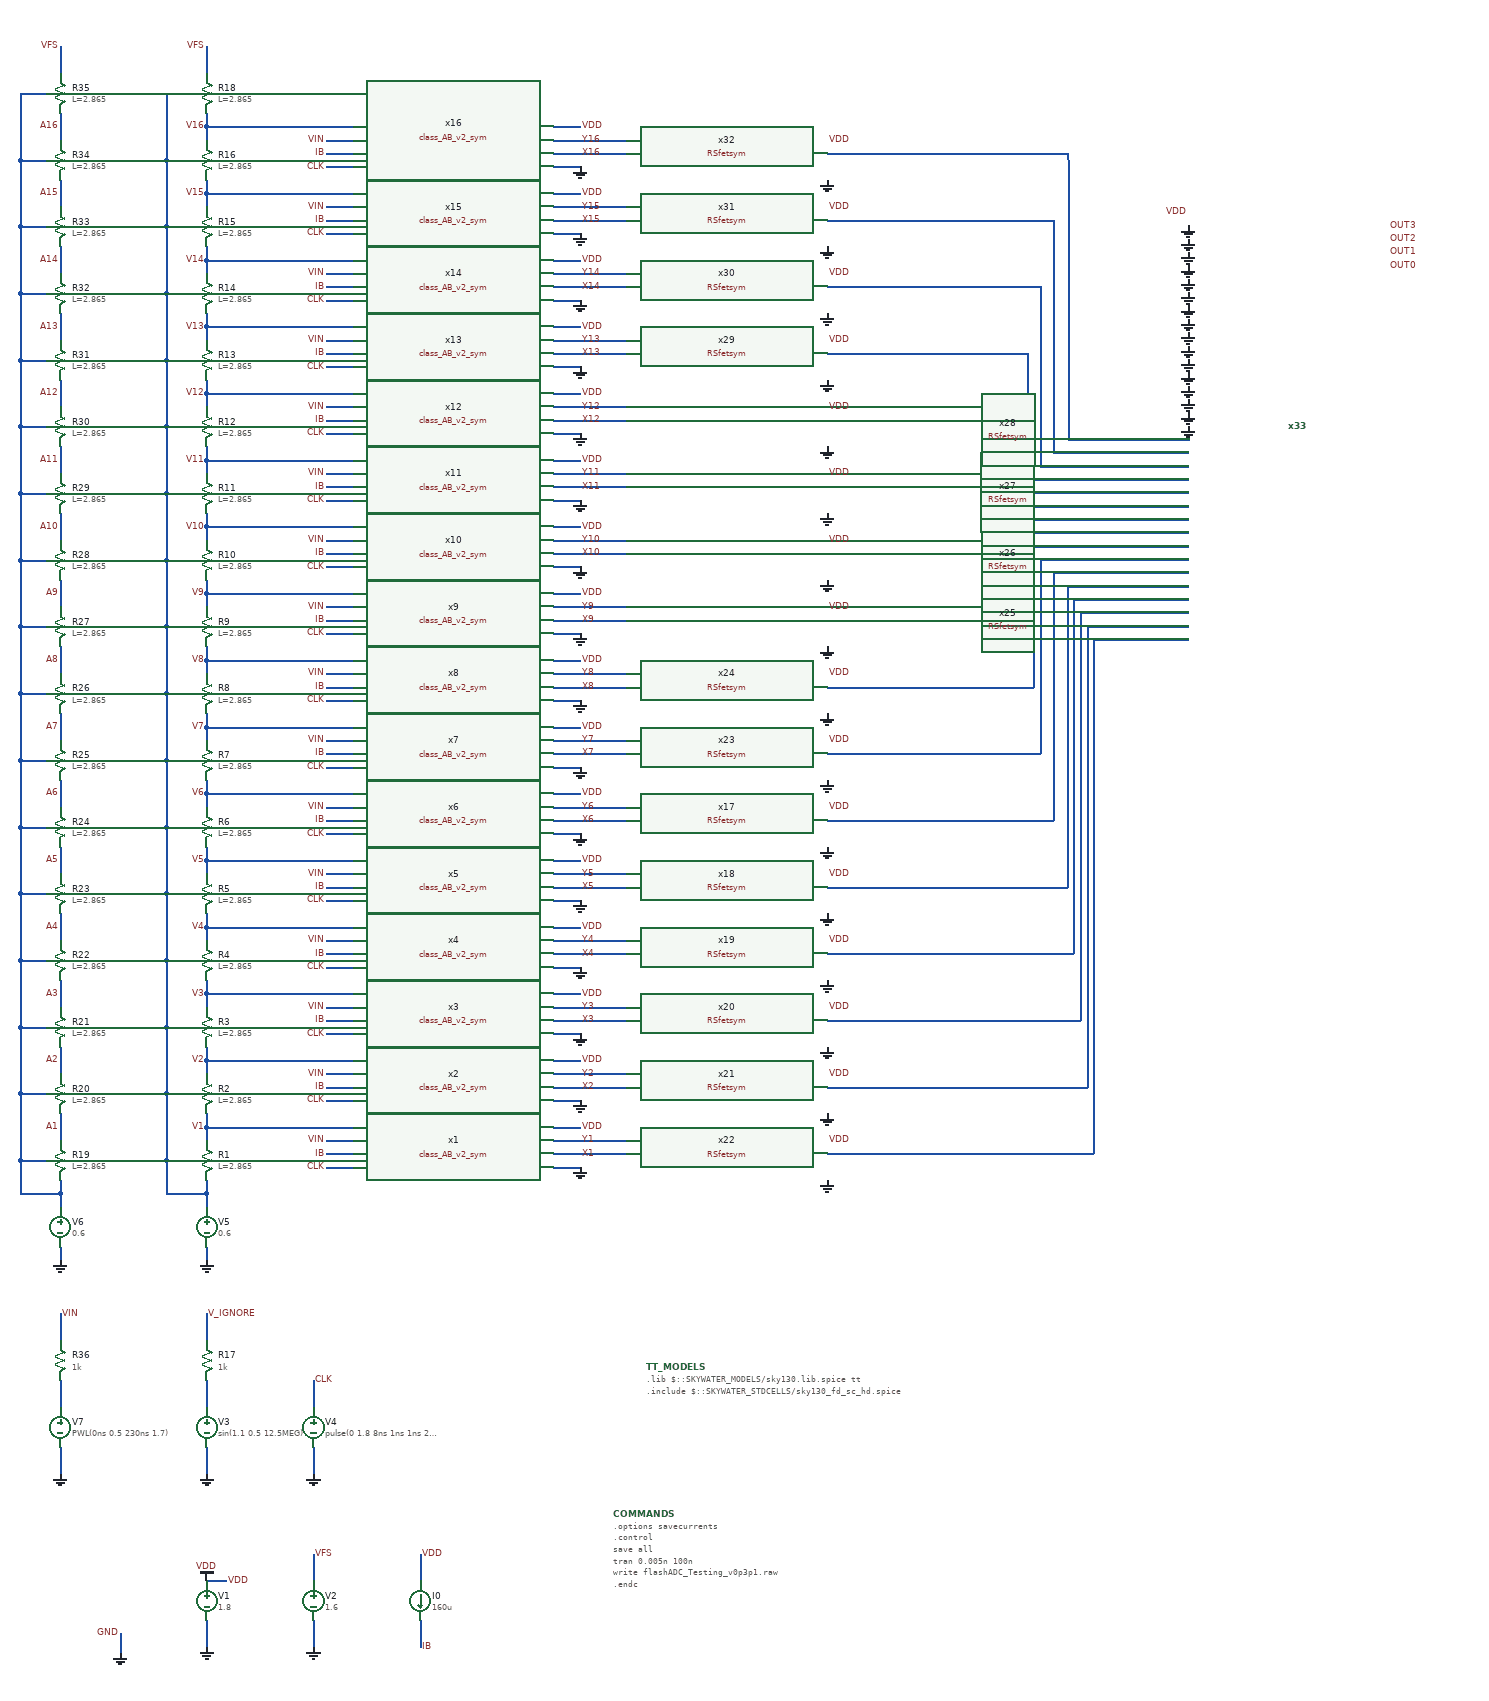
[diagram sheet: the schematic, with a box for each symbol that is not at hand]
v {xschem version=3.4.5 file_version=1.2
}
G {}
K {}
V {}
S {}
E {}
B 2 3025 -2178.75 3825 -1778.75 {flags=graph
y1=-0.36
y2=1.44
ypos1=0
ypos2=2
divy=5
subdivy=1
unity=1
x1=0
x2=1e-07
divx=5
subdivx=1
xlabmag=1.0
ylabmag=1.0


dataset=-1
unitx=1
logx=0
logy=0
color=4
node=clk}
B 2 3025 -2578.75 3825 -2178.75 {flags=graph
y1=-0.0013
y2=1.7
ypos1=0
ypos2=2
divy=5
subdivy=1
unity=1
x1=0
x2=1e-07
divx=5
subdivx=1
xlabmag=1.0
ylabmag=1.0


dataset=-1
unitx=1
logx=0
logy=0
color="4 5 6 8"
node="y1
v1
vin
a1"}
B 2 3025 -2978.75 3825 -2578.75 {flags=graph
y1=-0.0013
y2=1.7
ypos1=0
ypos2=2
divy=5
subdivy=1
unity=1
x1=0
x2=1e-07
divx=5
subdivx=1
xlabmag=1.0
ylabmag=1.0


dataset=-1
unitx=1
logx=0
logy=0




color="4 5 6 8"
node="y2
v2
vin
a2"}
B 2 3025 -3378.75 3825 -2978.75 {flags=graph
y1=-0.0013
y2=1.7
ypos1=0
ypos2=2
divy=5
subdivy=1
unity=1
x1=0
x2=1e-07
divx=5
subdivx=1
xlabmag=1.0
ylabmag=1.0


dataset=-1
unitx=1
logx=0
logy=0
color="4 5 6 8"
node="y3
v3
vin
a3"}
B 2 3025 -3778.75 3825 -3378.75 {flags=graph
y1=-0.0013
y2=1.9
ypos1=0
ypos2=2
divy=5
subdivy=1
unity=1
x1=0
x2=1e-07
divx=5
subdivx=1
xlabmag=1.0
ylabmag=1.0
node="y4
v4
vin
a4"
color="4 5 6 8"
dataset=-1
unitx=1
logx=0
logy=0
}
B 2 3825 -2578.75 4625 -2178.75 {flags=graph
y1=-0.0013
y2=1.9
ypos1=0
ypos2=2
divy=5
subdivy=1
unity=1
x1=0
x2=1e-07
divx=5
subdivx=1
xlabmag=1.0
ylabmag=1.0


dataset=-1
unitx=1
logx=0
logy=0

color="4 5 6 8"
node="y5
v5
vin
a5"}
B 2 3825 -2978.75 4625 -2578.75 {flags=graph
y1=-0.0013
y2=1.9
ypos1=0
ypos2=2
divy=5
subdivy=1
unity=1
x1=0
x2=1e-07
divx=5
subdivx=1
xlabmag=1.0
ylabmag=1.0
node="y6
v6
vin
a6"
color="4 5 6 8"
dataset=-1
unitx=1
logx=0
logy=0
}
B 2 3825 -3378.75 4625 -2978.75 {flags=graph
y1=-0.0013
y2=1.9
ypos1=0
ypos2=2
divy=5
subdivy=1
unity=1
x1=0
x2=1e-07
divx=5
subdivx=1
xlabmag=1.0
ylabmag=1.0


dataset=-1
unitx=1
logx=0
logy=0
color="4 5 6 8"
node="y7
v7
vin
a7"}
B 2 3825 -3778.75 4625 -3378.75 {flags=graph
y1=-0.0013
y2=1.9
ypos1=0
ypos2=2
divy=5
subdivy=1
unity=1
x1=0
x2=1e-07
divx=5
subdivx=1
xlabmag=1.0
ylabmag=1.0


dataset=-1
unitx=1
logx=0
logy=0
color="4 5 6 8"
node="y8
v8
vin
a8"}
B 2 4625 -2578.75 5425 -2178.75 {flags=graph
y1=-0.0013
y2=1.9
ypos1=0
ypos2=2
divy=5
subdivy=1
unity=1
x1=0
x2=1e-07
divx=5
subdivx=1
xlabmag=1.0
ylabmag=1.0


dataset=-1
unitx=1
logx=0
logy=0
color="4 5 6 8"
node="y9
v9
vin
a9"}
B 2 4625 -2978.75 5425 -2578.75 {flags=graph
y1=-0.12
y2=1.9
ypos1=0
ypos2=2
divy=5
subdivy=1
unity=1
x1=0
x2=1e-07
divx=5
subdivx=1
xlabmag=1.0
ylabmag=1.0


dataset=-1
unitx=1
logx=0
logy=0




color="4 5 6 8"
node="y10
v10
vin
a10"}
B 2 4625 -3378.75 5425 -2978.75 {flags=graph
y1=-0.0013
y2=1.9
ypos1=0
ypos2=2
divy=5
subdivy=1
unity=1
x1=0
x2=1e-07
divx=5
subdivx=1
xlabmag=1.0
ylabmag=1.0


dataset=-1
unitx=1
logx=0
logy=0
color="4 5 6 8"
node="y11
v11
vin
a11"}
B 2 4625 -3778.75 5425 -3378.75 {flags=graph
y1=-0.0013
y2=1.9
ypos1=0
ypos2=2
divy=5
subdivy=1
unity=1
x1=0
x2=1e-07
divx=5
subdivx=1
xlabmag=1.0
ylabmag=1.0
node="y12
v12
vin
a12"
color="4 5 6 8"
dataset=-1
unitx=1
logx=0
logy=0
}
B 2 5425 -2578.75 6225 -2178.75 {flags=graph
y1=-0.0011
y2=1.9
ypos1=0
ypos2=2
divy=5
subdivy=1
unity=1
x1=0
x2=1e-07
divx=5
subdivx=1
xlabmag=1.0
ylabmag=1.0


dataset=-1
unitx=1
logx=0
logy=0

color="4 5 6 8"
node="y13
v13
vin
a13"}
B 2 5425 -2978.75 6225 -2578.75 {flags=graph
y1=0.61
y2=1.9
ypos1=0
ypos2=2
divy=5
subdivy=1
unity=1
x1=0
x2=1e-07
divx=5
subdivx=1
xlabmag=1.0
ylabmag=1.0
node="y14
v14
vin
a14"
color="4 5 6 8"
dataset=-1
unitx=1
logx=0
logy=0
}
B 2 5425 -3378.75 6225 -2978.75 {flags=graph
y1=0.6
y2=1.9
ypos1=0
ypos2=2
divy=5
subdivy=1
unity=1
x1=0
x2=1e-07
divx=5
subdivx=1
xlabmag=1.0
ylabmag=1.0


dataset=-1
unitx=1
logx=0
logy=0
color="4 5 6 8"
node="y15
v15
vin
a15"}
B 2 5425 -3778.75 6225 -3378.75 {flags=graph
y1=0.6
y2=1.9
ypos1=0
ypos2=2
divy=5
subdivy=1
unity=1
x1=0
x2=1e-07
divx=5
subdivx=1
xlabmag=1.0
ylabmag=1.0


dataset=-1
unitx=1
logx=0
logy=0
color="4 5 6 8"
node="y16
v16
vin
a16"}
B 2 3825 -2178.75 4625 -1778.75 {flags=graph
y1=0
y2=1.8
ypos1=0
ypos2=2
divy=5
subdivy=1
unity=1
x1=0
x2=1e-07
divx=5
subdivx=1
xlabmag=1.0
ylabmag=1.0


dataset=-1
unitx=1
logx=0
logy=0
color=4
node=clk}
B 2 4625 -2178.75 5425 -1778.75 {flags=graph
y1=0
y2=1.8
ypos1=0
ypos2=2
divy=5
subdivy=1
unity=1
x1=0
x2=1e-07
divx=5
subdivx=1
xlabmag=1.0
ylabmag=1.0


dataset=-1
unitx=1
logx=0
logy=0
color=4
node=clk}
B 2 5425 -2178.75 6225 -1778.75 {flags=graph
y1=0
y2=1.8
ypos1=0
ypos2=2
divy=5
subdivy=1
unity=1
x1=0
x2=1e-07
divx=5
subdivx=1
xlabmag=1.0
ylabmag=1.0


dataset=-1
unitx=1
logx=0
logy=0
color=4
node=clk}
B 2 6225 -2578.75 7025 -2178.75 {flags=graph
y1=1.3
y2=1.4
ypos1=0
ypos2=2
divy=5
subdivy=1
unity=1
x1=0
x2=1e-07
divx=5
subdivx=1
xlabmag=1.0
ylabmag=1.0


dataset=-1
unitx=1
logx=0
logy=0

color="4 8"
node="v13
a13"}
B 2 1985 -4078.75 2785 -3678.75 {flags=graph
y1=-0.0013
y2=1.9
ypos1=0
ypos2=2
divy=5
subdivy=1
unity=1
x1=0
x2=1e-07
divx=5
subdivx=1
xlabmag=1.0
ylabmag=1.0
node="y6
x6
y6q
x6!q
Vin"
color="4 5 10 8 6"
dataset=-1
unitx=1
logx=0
logy=0
hilight_wave=3}
B 2 3025 -1208.75 3825 -808.75 {flags=graph
y1=-0.15
y2=2.1
ypos1=0
ypos2=2
divy=5
subdivy=1
unity=1
x1=0
x2=1e-07
divx=5
subdivx=1
xlabmag=1.0
ylabmag=1.0


dataset=-1
unitx=1
logx=0
logy=0

color="7 21 8 4"
node="out3
out2
out1
out0"}
B 2 3026.25 -1761.25 3825 -1318.75 {flags=graph
y1=0
y2=1.8
ypos1=0
ypos2=2
divy=5
subdivy=1
unity=1
x1=0
x2=1e-07
divx=5
subdivx=1
xlabmag=1.0
ylabmag=1.0


dataset=-1
unitx=1
logx=0
logy=0
color=4
node=clk
hilight_wave=0}
N 235 -428.75 235 -408.75 {
lab=V2}
N 235 -328.75 235 -308.75 {
lab=V1}
N 235 -228.75 235 -208.75 {
lab=#net1}
N 235 -528.75 235 -508.75 {
lab=V3}
N 235 -628.75 235 -608.75 {
lab=V4}
N 235 -728.75 235 -708.75 {
lab=V5}
N 235 -828.75 235 -808.75 {
lab=V6}
N 235 -928.75 235 -908.75 {
lab=V7}
N 235 -1028.75 235 -1008.75 {
lab=V8}
N 235 -1128.75 235 -1108.75 {
lab=V9}
N 235 -1228.75 235 -1208.75 {
lab=V10}
N 235 -1328.75 235 -1308.75 {
lab=V11}
N 235 -1428.75 235 -1408.75 {
lab=V12}
N 235 -1528.75 235 -1508.75 {
lab=V13}
N 235 -1628.75 235 -1608.75 {
lab=V14}
N 235 -1728.75 235 -1708.75 {
lab=V15}
N 235 -1828.75 235 -1808.75 {
lab=V16}
N 175 -1778.75 215 -1778.75 {
lab=#net1}
N 175 -1778.75 175 -1678.75 {
lab=#net1}
N 175 -1678.75 215 -1678.75 {
lab=#net1}
N 175 -1578.75 215 -1578.75 {
lab=#net1}
N 175 -1478.75 215 -1478.75 {
lab=#net1}
N 175 -1378.75 215 -1378.75 {
lab=#net1}
N 175 -1278.75 215 -1278.75 {
lab=#net1}
N 175 -1178.75 215 -1178.75 {
lab=#net1}
N 175 -1078.75 215 -1078.75 {
lab=#net1}
N 175 -978.75 215 -978.75 {
lab=#net1}
N 175 -878.75 215 -878.75 {
lab=#net1}
N 175 -778.75 215 -778.75 {
lab=#net1}
N 175 -678.75 215 -678.75 {
lab=#net1}
N 175 -578.75 215 -578.75 {
lab=#net1}
N 175 -478.75 215 -478.75 {
lab=#net1}
N 175 -378.75 215 -378.75 {
lab=#net1}
N 175 -278.75 215 -278.75 {
lab=#net1}
N 175 -228.75 235 -228.75 {
lab=#net1}
N 175 -278.75 175 -228.75 {
lab=#net1}
N 175 -478.75 175 -378.75 {
lab=#net1}
N 175 -578.75 175 -478.75 {
lab=#net1}
N 235 51.25 235 91.25 {
lab=#net2}
N 235 151.25 235 191.25 {
lab=GND}
N 395 51.25 395 91.25 {
lab=CLK}
N 395 151.25 395 191.25 {
lab=GND}
N 235 351.25 265 351.25 {
lab=VDD}
N 235 411.25 235 451.25 {
lab=GND}
N 395 311.25 395 351.25 {
lab=VFS}
N 395 411.25 395 451.25 {
lab=GND}
N 235 -48.75 235 -8.75 {
lab=V_IGNORE}
N 235 -328.75 455 -328.75 {
lab=V1}
N 235 -1948.75 235 -1908.75 {
lab=VFS}
N 175 -1878.75 215 -1878.75 {
lab=#net1}
N 175 -1878.75 175 -1778.75 {
lab=#net1}
N 415 -288.75 455 -288.75 {
lab=IB}
N 415 -308.75 455 -308.75 {
lab=VIN}
N 755 -328.75 795 -328.75 {
lab=VDD}
N 755 -308.75 865 -308.75 {
lab=Y1}
N 755 -288.75 865 -288.75 {
lab=X1}
N 755 -268.75 795 -268.75 {
lab=GND}
N 755 -428.75 795 -428.75 {
lab=VDD}
N 755 -408.75 865 -408.75 {
lab=Y2}
N 755 -388.75 865 -388.75 {
lab=X2}
N 755 -368.75 795 -368.75 {
lab=GND}
N 755 -528.75 795 -528.75 {
lab=VDD}
N 755 -508.75 865 -508.75 {
lab=Y3}
N 755 -488.75 865 -488.75 {
lab=X3}
N 755 -468.75 795 -468.75 {
lab=GND}
N 755 -628.75 795 -628.75 {
lab=VDD}
N 755 -608.75 865 -608.75 {
lab=Y4}
N 755 -588.75 865 -588.75 {
lab=X4}
N 755 -568.75 795 -568.75 {
lab=GND}
N 755 -728.75 795 -728.75 {
lab=VDD}
N 755 -708.75 865 -708.75 {
lab=Y5}
N 755 -688.75 865 -688.75 {
lab=X5}
N 755 -668.75 795 -668.75 {
lab=GND}
N 755 -828.75 795 -828.75 {
lab=VDD}
N 755 -808.75 865 -808.75 {
lab=Y6}
N 755 -788.75 865 -788.75 {
lab=X6}
N 755 -768.75 795 -768.75 {
lab=GND}
N 755 -928.75 795 -928.75 {
lab=VDD}
N 755 -908.75 865 -908.75 {
lab=Y7}
N 755 -888.75 865 -888.75 {
lab=X7}
N 755 -868.75 795 -868.75 {
lab=GND}
N 755 -1028.75 795 -1028.75 {
lab=VDD}
N 755 -1008.75 865 -1008.75 {
lab=Y8}
N 755 -988.75 865 -988.75 {
lab=X8}
N 755 -968.75 795 -968.75 {
lab=GND}
N 755 -1128.75 795 -1128.75 {
lab=VDD}
N 755 -1108.75 865 -1108.75 {
lab=Y9}
N 755 -1088.75 865 -1088.75 {
lab=X9}
N 755 -1068.75 795 -1068.75 {
lab=GND}
N 755 -1228.75 795 -1228.75 {
lab=VDD}
N 755 -1208.75 865 -1208.75 {
lab=Y10}
N 755 -1188.75 865 -1188.75 {
lab=X10}
N 755 -1168.75 795 -1168.75 {
lab=GND}
N 755 -1328.75 795 -1328.75 {
lab=VDD}
N 755 -1308.75 865 -1308.75 {
lab=Y11}
N 755 -1288.75 865 -1288.75 {
lab=X11}
N 755 -1268.75 795 -1268.75 {
lab=GND}
N 755 -1428.75 795 -1428.75 {
lab=VDD}
N 755 -1408.75 865 -1408.75 {
lab=Y12}
N 755 -1388.75 865 -1388.75 {
lab=X12}
N 755 -1368.75 795 -1368.75 {
lab=GND}
N 755 -1528.75 795 -1528.75 {
lab=VDD}
N 755 -1508.75 865 -1508.75 {
lab=Y13}
N 755 -1488.75 865 -1488.75 {
lab=X13}
N 755 -1468.75 795 -1468.75 {
lab=GND}
N 755 -1628.75 795 -1628.75 {
lab=VDD}
N 755 -1608.75 865 -1608.75 {
lab=Y14}
N 755 -1588.75 865 -1588.75 {
lab=X14}
N 755 -1568.75 795 -1568.75 {
lab=GND}
N 755 -1728.75 795 -1728.75 {
lab=VDD}
N 755 -1708.75 865 -1708.75 {
lab=Y15}
N 755 -1688.75 865 -1688.75 {
lab=X15}
N 755 -1668.75 795 -1668.75 {
lab=GND}
N 755 -1828.75 795 -1828.75 {
lab=VDD}
N 755 -1808.75 865 -1808.75 {
lab=Y16}
N 755 -1788.75 865 -1788.75 {
lab=X16}
N 755 -1768.75 795 -1768.75 {
lab=GND}
N 555 311.25 555 351.25 {
lab=VDD}
N 555 411.25 555 451.25 {
lab=IB}
N 235 -148.75 235 -128.75 {
lab=GND}
N 15 -448.75 15 -408.75 {
lab=A2}
N 15 -348.75 15 -308.75 {
lab=A1}
N 15 -228.75 15 -208.75 {
lab=#net3}
N 15 -548.75 15 -508.75 {
lab=A3}
N 15 -648.75 15 -608.75 {
lab=A4}
N 15 -748.75 15 -708.75 {
lab=A5}
N 15 -848.75 15 -808.75 {
lab=A6}
N 15 -948.75 15 -908.75 {
lab=A7}
N 15 -1048.75 15 -1008.75 {
lab=A8}
N 15 -1148.75 15 -1108.75 {
lab=A9}
N 15 -1248.75 15 -1208.75 {
lab=A10}
N 15 -1348.75 15 -1308.75 {
lab=A11}
N 15 -1448.75 15 -1408.75 {
lab=A12}
N 15 -1548.75 15 -1508.75 {
lab=A13}
N 15 -1648.75 15 -1608.75 {
lab=A14}
N 15 -1748.75 15 -1708.75 {
lab=A15}
N 15 -1848.75 15 -1808.75 {
lab=A16}
N -45 -1778.75 -5 -1778.75 {
lab=#net3}
N -45 -1778.75 -45 -1678.75 {
lab=#net3}
N -45 -1678.75 -5 -1678.75 {
lab=#net3}
N -45 -1578.75 -5 -1578.75 {
lab=#net3}
N -45 -1478.75 -5 -1478.75 {
lab=#net3}
N -45 -1378.75 -5 -1378.75 {
lab=#net3}
N -45 -1278.75 -5 -1278.75 {
lab=#net3}
N -45 -1178.75 -5 -1178.75 {
lab=#net3}
N -45 -1078.75 -5 -1078.75 {
lab=#net3}
N -45 -978.75 -5 -978.75 {
lab=#net3}
N -45 -878.75 -5 -878.75 {
lab=#net3}
N -45 -778.75 -5 -778.75 {
lab=#net3}
N -45 -678.75 -5 -678.75 {
lab=#net3}
N -45 -578.75 -5 -578.75 {
lab=#net3}
N -45 -478.75 -5 -478.75 {
lab=#net3}
N -45 -378.75 -5 -378.75 {
lab=#net3}
N -45 -278.75 -5 -278.75 {
lab=#net3}
N -45 -228.75 15 -228.75 {
lab=#net3}
N -45 -278.75 -45 -228.75 {
lab=#net3}
N -45 -478.75 -45 -378.75 {
lab=#net3}
N -45 -578.75 -45 -478.75 {
lab=#net3}
N 15 -1948.75 15 -1908.75 {
lab=VFS}
N -45 -1878.75 -5 -1878.75 {
lab=#net3}
N -45 -1878.75 -45 -1778.75 {
lab=#net3}
N 15 -148.75 15 -128.75 {
lab=GND}
N 415 -268.75 455 -268.75 {
lab=CLK}
N 235 -428.75 455 -428.75 {
lab=V2}
N 415 -388.75 455 -388.75 {
lab=IB}
N 415 -408.75 455 -408.75 {
lab=VIN}
N 415 -368.75 455 -368.75 {
lab=CLK}
N 235 -528.75 455 -528.75 {
lab=V3}
N 415 -488.75 455 -488.75 {
lab=IB}
N 415 -508.75 455 -508.75 {
lab=VIN}
N 415 -468.75 455 -468.75 {
lab=CLK}
N 235 -628.75 455 -628.75 {
lab=V4}
N 415 -588.75 455 -588.75 {
lab=IB}
N 415 -608.75 455 -608.75 {
lab=VIN}
N 415 -568.75 455 -568.75 {
lab=CLK}
N 235 -728.75 455 -728.75 {
lab=V5}
N 415 -688.75 455 -688.75 {
lab=IB}
N 415 -708.75 455 -708.75 {
lab=VIN}
N 415 -668.75 455 -668.75 {
lab=CLK}
N 235 -828.75 455 -828.75 {
lab=V6}
N 415 -788.75 455 -788.75 {
lab=IB}
N 415 -808.75 455 -808.75 {
lab=VIN}
N 415 -768.75 455 -768.75 {
lab=CLK}
N 235 -928.75 455 -928.75 {
lab=V7}
N 415 -888.75 455 -888.75 {
lab=IB}
N 415 -908.75 455 -908.75 {
lab=VIN}
N 415 -868.75 455 -868.75 {
lab=CLK}
N 235 -1028.75 455 -1028.75 {
lab=V8}
N 415 -988.75 455 -988.75 {
lab=IB}
N 415 -1008.75 455 -1008.75 {
lab=VIN}
N 415 -968.75 455 -968.75 {
lab=CLK}
N 235 -1128.75 455 -1128.75 {
lab=V9}
N 415 -1088.75 455 -1088.75 {
lab=IB}
N 415 -1108.75 455 -1108.75 {
lab=VIN}
N 415 -1068.75 455 -1068.75 {
lab=CLK}
N 235 -1228.75 455 -1228.75 {
lab=V10}
N 415 -1188.75 455 -1188.75 {
lab=IB}
N 415 -1208.75 455 -1208.75 {
lab=VIN}
N 415 -1168.75 455 -1168.75 {
lab=CLK}
N 235 -1328.75 455 -1328.75 {
lab=V11}
N 415 -1288.75 455 -1288.75 {
lab=IB}
N 415 -1308.75 455 -1308.75 {
lab=VIN}
N 415 -1268.75 455 -1268.75 {
lab=CLK}
N 235 -1428.75 455 -1428.75 {
lab=V12}
N 415 -1388.75 455 -1388.75 {
lab=IB}
N 415 -1408.75 455 -1408.75 {
lab=VIN}
N 415 -1368.75 455 -1368.75 {
lab=CLK}
N 235 -1528.75 455 -1528.75 {
lab=V13}
N 415 -1488.75 455 -1488.75 {
lab=IB}
N 415 -1508.75 455 -1508.75 {
lab=VIN}
N 415 -1468.75 455 -1468.75 {
lab=CLK}
N 235 -1628.75 455 -1628.75 {
lab=V14}
N 415 -1588.75 455 -1588.75 {
lab=IB}
N 415 -1608.75 455 -1608.75 {
lab=VIN}
N 415 -1568.75 455 -1568.75 {
lab=CLK}
N 235 -1728.75 455 -1728.75 {
lab=V15}
N 415 -1688.75 455 -1688.75 {
lab=IB}
N 415 -1708.75 455 -1708.75 {
lab=VIN}
N 415 -1668.75 455 -1668.75 {
lab=CLK}
N 235 -1828.75 455 -1828.75 {
lab=V16}
N 415 -1788.75 455 -1788.75 {
lab=IB}
N 415 -1808.75 455 -1808.75 {
lab=VIN}
N 415 -1768.75 455 -1768.75 {
lab=CLK}
N 15 51.25 15 91.25 {
lab=#net4}
N 15 151.25 15 191.25 {
lab=GND}
N 15 -48.75 15 -8.75 {
lab=VIN}
N 175 -1678.75 175 -1578.75 {
lab=#net1}
N 175 -1578.75 175 -1478.75 {
lab=#net1}
N 175 -1478.75 175 -1378.75 {
lab=#net1}
N 175 -1378.75 175 -1278.75 {
lab=#net1}
N 175 -1278.75 175 -1178.75 {
lab=#net1}
N 175 -1178.75 175 -1078.75 {
lab=#net1}
N 175 -1078.75 175 -978.75 {
lab=#net1}
N 175 -978.75 175 -878.75 {
lab=#net1}
N 175 -878.75 175 -778.75 {
lab=#net1}
N 175 -778.75 175 -678.75 {
lab=#net1}
N 175 -678.75 175 -578.75 {
lab=#net1}
N 175 -378.75 175 -278.75 {
lab=#net1}
N 235 -248.75 235 -228.75 {
lab=#net1}
N 235 -348.75 235 -328.75 {
lab=V1}
N -45 -1678.75 -45 -1578.75 {
lab=#net3}
N -45 -1578.75 -45 -1478.75 {
lab=#net3}
N -45 -1478.75 -45 -1378.75 {
lab=#net3}
N -45 -1378.75 -45 -1278.75 {
lab=#net3}
N -45 -1278.75 -45 -1178.75 {
lab=#net3}
N -45 -1178.75 -45 -1078.75 {
lab=#net3}
N -45 -1078.75 -45 -978.75 {
lab=#net3}
N -45 -978.75 -45 -878.75 {
lab=#net3}
N -45 -878.75 -45 -778.75 {
lab=#net3}
N -45 -778.75 -45 -678.75 {
lab=#net3}
N -45 -678.75 -45 -578.75 {
lab=#net3}
N -45 -378.75 -45 -278.75 {
lab=#net3}
N 15 -248.75 15 -228.75 {
lab=#net3}
N 235 -448.75 235 -428.75 {
lab=V2}
N 235 -548.75 235 -528.75 {
lab=V3}
N 235 -648.75 235 -628.75 {
lab=V4}
N 235 -748.75 235 -728.75 {
lab=V5}
N 235 -848.75 235 -828.75 {
lab=V6}
N 235 -948.75 235 -928.75 {
lab=V7}
N 235 -1048.75 235 -1028.75 {
lab=V8}
N 235 -1148.75 235 -1128.75 {
lab=V9}
N 235 -1248.75 235 -1228.75 {
lab=V10}
N 235 -1348.75 235 -1328.75 {
lab=V11}
N 235 -1448.75 235 -1428.75 {
lab=V12}
N 235 -1548.75 235 -1528.75 {
lab=V13}
N 235 -1648.75 235 -1628.75 {
lab=V14}
N 235 -1748.75 235 -1728.75 {
lab=V15}
N 235 -1848.75 235 -1828.75 {
lab=V16}
N 1435 -1238.75 1435 -1188.75 {
lab=#net5}
N 1455 -1218.75 1455 -1088.75 {
lab=#net6}
N 1475 -1198.75 1475 -988.75 {
lab=#net7}
N 1485 -1178.75 1485 -888.75 {
lab=#net8}
N 1505 -1158.75 1505 -788.75 {
lab=#net9}
N 1525 -1138.75 1525 -688.75 {
lab=#net10}
N 1535 -1118.75 1535 -588.75 {
lab=#net11}
N 1545 -1088.75 1545 -488.75 {
lab=#net12}
N 1545 -1098.75 1545 -1088.75 {
lab=#net12}
N 1555 -1078.75 1555 -388.75 {
lab=#net13}
N 1565 -1058.75 1565 -288.75 {
lab=#net14}
N 1165 -1788.75 1525 -1788.75 {
lab=#net15}
N 1525 -1788.75 1526.25 -1768.75 {
lab=#net15}
N 1165 -1688.75 1505 -1688.75 {
lab=#net16}
N 1505 -1688.75 1505 -1668.75 {
lab=#net16}
N 1165 -1588.75 1485 -1588.75 {
lab=#net17}
N 1485 -1588.75 1485 -1568.75 {
lab=#net17}
N 1165 -1488.75 1465 -1488.75 {
lab=#net18}
N 1465 -1488.75 1465 -1470 {
lab=#net18}
N 1165 -1388.75 1445 -1388.75 {
lab=#net19}
N 1445 -1388.75 1445 -1368.75 {
lab=#net19}
N 1165 -1288.75 1425 -1288.75 {
lab=#net20}
N 1425 -1288.75 1425 -1268.75 {
lab=#net20}
N 1165 -1188.75 1435 -1188.75 {
lab=#net5}
N 1165 -1088.75 1455 -1088.75 {
lab=#net6}
N 1165 -988.75 1475 -988.75 {
lab=#net7}
N 1165 -888.75 1485 -888.75 {
lab=#net8}
N 1165 -788.75 1505 -788.75 {
lab=#net9}
N 1165 -688.75 1525 -688.75 {
lab=#net10}
N 1165 -588.75 1535 -588.75 {
lab=#net11}
N 1165 -488.75 1545 -488.75 {
lab=#net12}
N 1165 -388.75 1555 -388.75 {
lab=#net13}
N 1165 -288.75 1565 -288.75 {
lab=#net14}
N 105 430 105 460 {
lab=GND}
N 1565 -1060 1565 -1058.75 {
lab=#net14}
N 1565 -1060 1707.5 -1060 {
lab=#net14}
N 1555 -1080 1555 -1078.75 {
lab=#net13}
N 1555 -1080 1706.25 -1080 {
lab=#net13}
N 1545 -1100 1545 -1098.75 {
lab=#net12}
N 1545 -1100 1706.25 -1100 {
lab=#net12}
N 1535 -1120 1535 -1118.75 {
lab=#net11}
N 1535 -1120 1707.5 -1120 {
lab=#net11}
N 1525 -1140 1525 -1138.75 {
lab=#net10}
N 1525 -1140 1706.25 -1140 {
lab=#net10}
N 1505 -1160 1505 -1158.75 {
lab=#net9}
N 1505 -1160 1706.25 -1160 {
lab=#net9}
N 1485 -1180 1485 -1178.75 {
lab=#net8}
N 1485 -1180 1707.5 -1180 {
lab=#net8}
N 1475 -1200 1475 -1198.75 {
lab=#net7}
N 1475 -1200 1706.25 -1200 {
lab=#net7}
N 1455 -1220 1706.25 -1220 {
lab=#net6}
N 1455 -1220 1455 -1218.75 {
lab=#net6}
N 1435 -1240 1706.25 -1240 {
lab=#net5}
N 1435 -1240 1435 -1238.75 {
lab=#net5}
N 1425 -1260 1706.25 -1260 {
lab=#net20}
N 1425 -1268.75 1425 -1260 {
lab=#net20}
N 1445 -1280 1706.25 -1280 {
lab=#net19}
N 1445 -1368.75 1445 -1280 {
lab=#net19}
N 1465 -1300 1706.25 -1300 {
lab=#net18}
N 1465 -1470 1465 -1300 {
lab=#net18}
N 1485 -1568.75 1485 -1320 {
lab=#net17}
N 1485 -1320 1706.25 -1320 {
lab=#net17}
N 1505 -1668.75 1505 -1340 {
lab=#net16}
N 1505 -1340 1706.25 -1340 {
lab=#net16}
N 1526.25 -1768.75 1526.25 -1360 {
lab=#net15}
N 1526.25 -1360 1708.75 -1360 {
lab=#net15}
C {devices/vsource.sym} 235 121.25 0 0 {name=V3 value="sin(1.1 0.5 12.5MEG)" savecurrent=false}
C {devices/gnd.sym} 235 191.25 0 0 {name=l34 lab=GND}
C {devices/lab_pin.sym} 235 -48.75 2 0 {name=p196 sig_type=std_logic lab=V_IGNORE}
C {devices/vsource.sym} 395 121.25 0 0 {name=V4 value="pulse(0 1.8 8ns 1ns 1ns 20ns 40ns)" savecurrent=false}
C {devices/gnd.sym} 395 191.25 0 0 {name=l35 lab=GND}
C {devices/lab_pin.sym} 395 51.25 2 0 {name=p197 sig_type=std_logic lab=CLK}
C {devices/vsource.sym} 235 381.25 0 0 {name=V1 value=1.8 savecurrent=false}
C {devices/gnd.sym} 235 451.25 0 0 {name=l36 lab=GND}
C {devices/lab_pin.sym} 265 351.25 2 0 {name=p198 sig_type=std_logic lab=VDD}
C {devices/vsource.sym} 395 381.25 0 0 {name=V2 value=1.6 savecurrent=false}
C {devices/gnd.sym} 395 451.25 0 0 {name=l37 lab=GND}
C {devices/lab_pin.sym} 395 311.25 2 0 {name=p199 sig_type=std_logic lab=VFS}
C {devices/res.sym} 235 21.25 0 0 {name=R17
value=1k
footprint=1206
device=resistor
m=1}
C {devices/lab_pin.sym} 235 -1948.75 2 1 {name=p1 sig_type=std_logic lab=VFS}
C {devices/lab_pin.sym} 415 -288.75 2 1 {name=p40 sig_type=std_logic lab=IB}
C {devices/lab_pin.sym} 415 -268.75 2 1 {name=p41 sig_type=std_logic lab=CLK}
C {devices/lab_pin.sym} 415 -308.75 2 1 {name=p49 sig_type=std_logic lab=VIN}
C {devices/gnd.sym} 795 -268.75 0 0 {name=l1 lab=GND}
C {devices/lab_pin.sym} 795 -328.75 2 0 {name=p50 sig_type=std_logic lab=VDD}
C {devices/lab_pin.sym} 795 -308.75 2 0 {name=p51 sig_type=std_logic lab=Y1}
C {devices/lab_pin.sym} 795 -288.75 2 0 {name=p52 sig_type=std_logic lab=X1}
C {devices/gnd.sym} 795 -368.75 0 0 {name=l3 lab=GND}
C {devices/lab_pin.sym} 795 -428.75 2 0 {name=p53 sig_type=std_logic lab=VDD}
C {devices/lab_pin.sym} 795 -408.75 2 0 {name=p54 sig_type=std_logic lab=Y2}
C {devices/lab_pin.sym} 795 -388.75 2 0 {name=p55 sig_type=std_logic lab=X2}
C {devices/gnd.sym} 795 -468.75 0 0 {name=l4 lab=GND}
C {devices/lab_pin.sym} 795 -528.75 2 0 {name=p56 sig_type=std_logic lab=VDD}
C {devices/lab_pin.sym} 795 -508.75 2 0 {name=p57 sig_type=std_logic lab=Y3}
C {devices/lab_pin.sym} 795 -488.75 2 0 {name=p58 sig_type=std_logic lab=X3}
C {devices/gnd.sym} 795 -568.75 0 0 {name=l5 lab=GND}
C {devices/lab_pin.sym} 795 -628.75 2 0 {name=p59 sig_type=std_logic lab=VDD}
C {devices/lab_pin.sym} 795 -608.75 2 0 {name=p60 sig_type=std_logic lab=Y4}
C {devices/lab_pin.sym} 795 -588.75 2 0 {name=p61 sig_type=std_logic lab=X4}
C {devices/gnd.sym} 795 -668.75 0 0 {name=l6 lab=GND}
C {devices/lab_pin.sym} 795 -728.75 2 0 {name=p62 sig_type=std_logic lab=VDD}
C {devices/lab_pin.sym} 795 -708.75 2 0 {name=p63 sig_type=std_logic lab=Y5}
C {devices/lab_pin.sym} 795 -688.75 2 0 {name=p64 sig_type=std_logic lab=X5}
C {devices/gnd.sym} 795 -768.75 0 0 {name=l7 lab=GND}
C {devices/lab_pin.sym} 795 -828.75 2 0 {name=p65 sig_type=std_logic lab=VDD}
C {devices/lab_pin.sym} 795 -808.75 2 0 {name=p66 sig_type=std_logic lab=Y6}
C {devices/lab_pin.sym} 795 -788.75 2 0 {name=p67 sig_type=std_logic lab=X6}
C {devices/gnd.sym} 795 -868.75 0 0 {name=l8 lab=GND}
C {devices/lab_pin.sym} 795 -928.75 2 0 {name=p68 sig_type=std_logic lab=VDD}
C {devices/lab_pin.sym} 795 -908.75 2 0 {name=p69 sig_type=std_logic lab=Y7}
C {devices/lab_pin.sym} 795 -888.75 2 0 {name=p70 sig_type=std_logic lab=X7}
C {devices/gnd.sym} 795 -968.75 0 0 {name=l9 lab=GND}
C {devices/lab_pin.sym} 795 -1028.75 2 0 {name=p71 sig_type=std_logic lab=VDD}
C {devices/lab_pin.sym} 795 -1008.75 2 0 {name=p72 sig_type=std_logic lab=Y8}
C {devices/lab_pin.sym} 795 -988.75 2 0 {name=p73 sig_type=std_logic lab=X8}
C {devices/gnd.sym} 795 -1068.75 0 0 {name=l10 lab=GND}
C {devices/lab_pin.sym} 795 -1128.75 2 0 {name=p74 sig_type=std_logic lab=VDD}
C {devices/lab_pin.sym} 795 -1108.75 2 0 {name=p75 sig_type=std_logic lab=Y9}
C {devices/lab_pin.sym} 795 -1088.75 2 0 {name=p76 sig_type=std_logic lab=X9}
C {devices/gnd.sym} 795 -1168.75 0 0 {name=l11 lab=GND}
C {devices/lab_pin.sym} 795 -1228.75 2 0 {name=p77 sig_type=std_logic lab=VDD}
C {devices/lab_pin.sym} 795 -1208.75 2 0 {name=p78 sig_type=std_logic lab=Y10}
C {devices/lab_pin.sym} 795 -1188.75 2 0 {name=p79 sig_type=std_logic lab=X10}
C {devices/gnd.sym} 795 -1268.75 0 0 {name=l12 lab=GND}
C {devices/lab_pin.sym} 795 -1328.75 2 0 {name=p80 sig_type=std_logic lab=VDD}
C {devices/lab_pin.sym} 795 -1308.75 2 0 {name=p81 sig_type=std_logic lab=Y11}
C {devices/lab_pin.sym} 795 -1288.75 2 0 {name=p82 sig_type=std_logic lab=X11}
C {devices/gnd.sym} 795 -1368.75 0 0 {name=l13 lab=GND}
C {devices/lab_pin.sym} 795 -1428.75 2 0 {name=p83 sig_type=std_logic lab=VDD}
C {devices/lab_pin.sym} 795 -1408.75 2 0 {name=p84 sig_type=std_logic lab=Y12}
C {devices/lab_pin.sym} 795 -1388.75 2 0 {name=p85 sig_type=std_logic lab=X12}
C {devices/gnd.sym} 795 -1468.75 0 0 {name=l14 lab=GND}
C {devices/lab_pin.sym} 795 -1528.75 2 0 {name=p86 sig_type=std_logic lab=VDD}
C {devices/lab_pin.sym} 795 -1508.75 2 0 {name=p87 sig_type=std_logic lab=Y13}
C {devices/lab_pin.sym} 795 -1488.75 2 0 {name=p88 sig_type=std_logic lab=X13}
C {devices/gnd.sym} 795 -1568.75 0 0 {name=l15 lab=GND}
C {devices/lab_pin.sym} 795 -1628.75 2 0 {name=p89 sig_type=std_logic lab=VDD}
C {devices/lab_pin.sym} 795 -1608.75 2 0 {name=p90 sig_type=std_logic lab=Y14}
C {devices/lab_pin.sym} 795 -1588.75 2 0 {name=p91 sig_type=std_logic lab=X14}
C {devices/gnd.sym} 795 -1668.75 0 0 {name=l16 lab=GND}
C {devices/lab_pin.sym} 795 -1728.75 2 0 {name=p92 sig_type=std_logic lab=VDD}
C {devices/lab_pin.sym} 795 -1708.75 2 0 {name=p93 sig_type=std_logic lab=Y15}
C {devices/lab_pin.sym} 795 -1688.75 2 0 {name=p94 sig_type=std_logic lab=X15}
C {devices/gnd.sym} 795 -1768.75 0 0 {name=l17 lab=GND}
C {devices/lab_pin.sym} 795 -1828.75 2 0 {name=p95 sig_type=std_logic lab=VDD}
C {devices/lab_pin.sym} 795 -1808.75 2 0 {name=p96 sig_type=std_logic lab=Y16}
C {devices/lab_pin.sym} 795 -1788.75 2 0 {name=p97 sig_type=std_logic lab=X16}
C {devices/lab_pin.sym} 235 -328.75 2 1 {name=p98 sig_type=std_logic lab=V1}
C {devices/lab_pin.sym} 235 -428.75 2 1 {name=p99 sig_type=std_logic lab=V2}
C {devices/lab_pin.sym} 235 -528.75 2 1 {name=p100 sig_type=std_logic lab=V3}
C {devices/lab_pin.sym} 235 -628.75 2 1 {name=p101 sig_type=std_logic lab=V4}
C {devices/lab_pin.sym} 235 -728.75 2 1 {name=p102 sig_type=std_logic lab=V5}
C {devices/lab_pin.sym} 235 -828.75 2 1 {name=p103 sig_type=std_logic lab=V6}
C {devices/lab_pin.sym} 235 -928.75 2 1 {name=p104 sig_type=std_logic lab=V7}
C {devices/lab_pin.sym} 235 -1028.75 2 1 {name=p105 sig_type=std_logic lab=V8}
C {devices/lab_pin.sym} 235 -1128.75 2 1 {name=p106 sig_type=std_logic lab=V9}
C {devices/lab_pin.sym} 235 -1228.75 2 1 {name=p107 sig_type=std_logic lab=V10}
C {devices/lab_pin.sym} 235 -1328.75 2 1 {name=p108 sig_type=std_logic lab=V11}
C {devices/lab_pin.sym} 235 -1428.75 2 1 {name=p109 sig_type=std_logic lab=V12}
C {devices/lab_pin.sym} 235 -1528.75 2 1 {name=p110 sig_type=std_logic lab=V13}
C {devices/lab_pin.sym} 235 -1628.75 2 1 {name=p111 sig_type=std_logic lab=V14}
C {devices/lab_pin.sym} 235 -1728.75 2 1 {name=p112 sig_type=std_logic lab=V15}
C {devices/lab_pin.sym} 235 -1828.75 2 1 {name=p113 sig_type=std_logic lab=V16}
C {devices/code_shown.sym} 845 251.25 0 0 {name=COMMANDS only_toplevel=false value=
"
.options savecurrents
.control

save all

tran 0.005n 100n
write flashADC_Testing_v0p3p1.raw

.endc
"}
C {devices/isource.sym} 555 381.25 0 0 {name=I0 value=160u}
C {devices/lab_pin.sym} 555 311.25 2 0 {name=p114 sig_type=std_logic lab=VDD}
C {devices/lab_pin.sym} 555 451.25 2 0 {name=p115 sig_type=std_logic lab=IB}
C {devices/vsource.sym} 235 -178.75 0 0 {name=V5 value=0.6 savecurrent=false}
C {devices/gnd.sym} 235 -128.75 0 0 {name=l2 lab=GND}
C {sky130_fd_pr/res_xhigh_po_5p73.sym} 15 -278.75 0 0 {name=R19
L=2.865
model=res_xhigh_po_5p73
spiceprefix=X
mult=8}
C {devices/lab_pin.sym} 15 -1948.75 2 1 {name=p116 sig_type=std_logic lab=VFS}
C {devices/lab_pin.sym} 15 -328.75 2 1 {name=p117 sig_type=std_logic lab=A1}
C {devices/lab_pin.sym} 15 -428.75 2 1 {name=p118 sig_type=std_logic lab=A2}
C {devices/lab_pin.sym} 15 -528.75 2 1 {name=p119 sig_type=std_logic lab=A3}
C {devices/lab_pin.sym} 15 -628.75 2 1 {name=p120 sig_type=std_logic lab=A4}
C {devices/lab_pin.sym} 15 -728.75 2 1 {name=p121 sig_type=std_logic lab=A5}
C {devices/lab_pin.sym} 15 -828.75 2 1 {name=p122 sig_type=std_logic lab=A6}
C {devices/lab_pin.sym} 15 -928.75 2 1 {name=p123 sig_type=std_logic lab=A7}
C {devices/lab_pin.sym} 15 -1028.75 2 1 {name=p124 sig_type=std_logic lab=A8}
C {devices/lab_pin.sym} 15 -1128.75 2 1 {name=p125 sig_type=std_logic lab=A9}
C {devices/lab_pin.sym} 15 -1228.75 2 1 {name=p126 sig_type=std_logic lab=A10}
C {devices/lab_pin.sym} 15 -1328.75 2 1 {name=p127 sig_type=std_logic lab=A11}
C {devices/lab_pin.sym} 15 -1428.75 2 1 {name=p128 sig_type=std_logic lab=A12}
C {devices/lab_pin.sym} 15 -1528.75 2 1 {name=p129 sig_type=std_logic lab=A13}
C {devices/lab_pin.sym} 15 -1628.75 2 1 {name=p130 sig_type=std_logic lab=A14}
C {devices/lab_pin.sym} 15 -1728.75 2 1 {name=p131 sig_type=std_logic lab=A15}
C {devices/lab_pin.sym} 15 -1828.75 2 1 {name=p132 sig_type=std_logic lab=A16}
C {devices/vsource.sym} 15 -178.75 0 0 {name=V6 value=0.6 savecurrent=false}
C {devices/gnd.sym} 15 -128.75 0 0 {name=l18 lab=GND}
C {sky130_fd_pr/res_xhigh_po_5p73.sym} 15 -378.75 0 0 {name=R20
L=2.865
model=res_xhigh_po_5p73
spiceprefix=X
mult=8}
C {sky130_fd_pr/res_xhigh_po_5p73.sym} 15 -478.75 0 0 {name=R21
L=2.865
model=res_xhigh_po_5p73
spiceprefix=X
mult=8}
C {sky130_fd_pr/res_xhigh_po_5p73.sym} 15 -578.75 0 0 {name=R22
L=2.865
model=res_xhigh_po_5p73
spiceprefix=X
mult=8}
C {sky130_fd_pr/res_xhigh_po_5p73.sym} 15 -678.75 0 0 {name=R23
L=2.865
model=res_xhigh_po_5p73
spiceprefix=X
mult=8}
C {sky130_fd_pr/res_xhigh_po_5p73.sym} 15 -778.75 0 0 {name=R24
L=2.865
model=res_xhigh_po_5p73
spiceprefix=X
mult=8}
C {sky130_fd_pr/res_xhigh_po_5p73.sym} 15 -878.75 0 0 {name=R25
L=2.865
model=res_xhigh_po_5p73
spiceprefix=X
mult=8}
C {sky130_fd_pr/res_xhigh_po_5p73.sym} 15 -978.75 0 0 {name=R26
L=2.865
model=res_xhigh_po_5p73
spiceprefix=X
mult=8}
C {sky130_fd_pr/res_xhigh_po_5p73.sym} 15 -1078.75 0 0 {name=R27
L=2.865
model=res_xhigh_po_5p73
spiceprefix=X
mult=8}
C {sky130_fd_pr/res_xhigh_po_5p73.sym} 15 -1178.75 0 0 {name=R28
L=2.865
model=res_xhigh_po_5p73
spiceprefix=X
mult=8}
C {sky130_fd_pr/res_xhigh_po_5p73.sym} 15 -1278.75 0 0 {name=R29
L=2.865
model=res_xhigh_po_5p73
spiceprefix=X
mult=8}
C {sky130_fd_pr/res_xhigh_po_5p73.sym} 15 -1378.75 0 0 {name=R30
L=2.865
model=res_xhigh_po_5p73
spiceprefix=X
mult=8}
C {sky130_fd_pr/res_xhigh_po_5p73.sym} 15 -1478.75 0 0 {name=R31
L=2.865
model=res_xhigh_po_5p73
spiceprefix=X
mult=8}
C {sky130_fd_pr/res_xhigh_po_5p73.sym} 15 -1578.75 0 0 {name=R32
L=2.865
model=res_xhigh_po_5p73
spiceprefix=X
mult=8}
C {sky130_fd_pr/res_xhigh_po_5p73.sym} 15 -1678.75 0 0 {name=R33
L=2.865
model=res_xhigh_po_5p73
spiceprefix=X
mult=8}
C {sky130_fd_pr/res_xhigh_po_5p73.sym} 15 -1778.75 0 0 {name=R34
L=2.865
model=res_xhigh_po_5p73
spiceprefix=X
mult=8}
C {sky130_fd_pr/res_xhigh_po_5p73.sym} 15 -1878.75 0 0 {name=R35
L=2.865
model=res_xhigh_po_5p73
spiceprefix=X
mult=8}
C {sky130_fd_pr/res_xhigh_po_5p73.sym} 235 -278.75 0 0 {name=R1
L=2.865
model=res_xhigh_po_5p73
spiceprefix=X
mult=8}
C {sky130_fd_pr/res_xhigh_po_5p73.sym} 235 -378.75 0 0 {name=R2
L=2.865
model=res_xhigh_po_5p73
spiceprefix=X
mult=8}
C {sky130_fd_pr/res_xhigh_po_5p73.sym} 235 -478.75 0 0 {name=R3
L=2.865
model=res_xhigh_po_5p73
spiceprefix=X
mult=8}
C {sky130_fd_pr/res_xhigh_po_5p73.sym} 235 -578.75 0 0 {name=R4
L=2.865
model=res_xhigh_po_5p73
spiceprefix=X
mult=8}
C {sky130_fd_pr/res_xhigh_po_5p73.sym} 235 -678.75 0 0 {name=R5
L=2.865
model=res_xhigh_po_5p73
spiceprefix=X
mult=8}
C {sky130_fd_pr/res_xhigh_po_5p73.sym} 235 -778.75 0 0 {name=R6
L=2.865
model=res_xhigh_po_5p73
spiceprefix=X
mult=8}
C {sky130_fd_pr/res_xhigh_po_5p73.sym} 235 -878.75 0 0 {name=R7
L=2.865
model=res_xhigh_po_5p73
spiceprefix=X
mult=8}
C {sky130_fd_pr/res_xhigh_po_5p73.sym} 235 -978.75 0 0 {name=R8
L=2.865
model=res_xhigh_po_5p73
spiceprefix=X
mult=8}
C {sky130_fd_pr/res_xhigh_po_5p73.sym} 235 -1078.75 0 0 {name=R9
L=2.865
model=res_xhigh_po_5p73
spiceprefix=X
mult=8}
C {sky130_fd_pr/res_xhigh_po_5p73.sym} 235 -1178.75 0 0 {name=R10
L=2.865
model=res_xhigh_po_5p73
spiceprefix=X
mult=8}
C {sky130_fd_pr/res_xhigh_po_5p73.sym} 235 -1278.75 0 0 {name=R11
L=2.865
model=res_xhigh_po_5p73
spiceprefix=X
mult=8}
C {sky130_fd_pr/res_xhigh_po_5p73.sym} 235 -1378.75 0 0 {name=R12
L=2.865
model=res_xhigh_po_5p73
spiceprefix=X
mult=8}
C {sky130_fd_pr/res_xhigh_po_5p73.sym} 235 -1478.75 0 0 {name=R13
L=2.865
model=res_xhigh_po_5p73
spiceprefix=X
mult=8}
C {sky130_fd_pr/res_xhigh_po_5p73.sym} 235 -1578.75 0 0 {name=R14
L=2.865
model=res_xhigh_po_5p73
spiceprefix=X
mult=8}
C {sky130_fd_pr/res_xhigh_po_5p73.sym} 235 -1678.75 0 0 {name=R15
L=2.865
model=res_xhigh_po_5p73
spiceprefix=X
mult=8}
C {sky130_fd_pr/res_xhigh_po_5p73.sym} 235 -1778.75 0 0 {name=R16
L=2.865
model=res_xhigh_po_5p73
spiceprefix=X
mult=8}
C {sky130_fd_pr/res_xhigh_po_5p73.sym} 235 -1878.75 0 0 {name=R18
L=2.865
model=res_xhigh_po_5p73
spiceprefix=X
mult=8}
C {devices/lab_pin.sym} 415 -388.75 2 1 {name=p2 sig_type=std_logic lab=IB}
C {devices/lab_pin.sym} 415 -368.75 2 1 {name=p3 sig_type=std_logic lab=CLK}
C {devices/lab_pin.sym} 415 -408.75 2 1 {name=p4 sig_type=std_logic lab=VIN}
C {devices/lab_pin.sym} 415 -488.75 2 1 {name=p5 sig_type=std_logic lab=IB}
C {devices/lab_pin.sym} 415 -468.75 2 1 {name=p6 sig_type=std_logic lab=CLK}
C {devices/lab_pin.sym} 415 -508.75 2 1 {name=p7 sig_type=std_logic lab=VIN}
C {devices/lab_pin.sym} 415 -588.75 2 1 {name=p8 sig_type=std_logic lab=IB}
C {devices/lab_pin.sym} 415 -568.75 2 1 {name=p9 sig_type=std_logic lab=CLK}
C {devices/lab_pin.sym} 415 -608.75 2 1 {name=p10 sig_type=std_logic lab=VIN}
C {devices/lab_pin.sym} 415 -688.75 2 1 {name=p11 sig_type=std_logic lab=IB}
C {devices/lab_pin.sym} 415 -668.75 2 1 {name=p12 sig_type=std_logic lab=CLK}
C {devices/lab_pin.sym} 415 -708.75 2 1 {name=p13 sig_type=std_logic lab=VIN}
C {devices/lab_pin.sym} 415 -788.75 2 1 {name=p14 sig_type=std_logic lab=IB}
C {devices/lab_pin.sym} 415 -768.75 2 1 {name=p15 sig_type=std_logic lab=CLK}
C {devices/lab_pin.sym} 415 -808.75 2 1 {name=p16 sig_type=std_logic lab=VIN}
C {devices/lab_pin.sym} 415 -888.75 2 1 {name=p17 sig_type=std_logic lab=IB}
C {devices/lab_pin.sym} 415 -868.75 2 1 {name=p18 sig_type=std_logic lab=CLK}
C {devices/lab_pin.sym} 415 -908.75 2 1 {name=p19 sig_type=std_logic lab=VIN}
C {devices/lab_pin.sym} 415 -988.75 2 1 {name=p20 sig_type=std_logic lab=IB}
C {devices/lab_pin.sym} 415 -968.75 2 1 {name=p21 sig_type=std_logic lab=CLK}
C {devices/lab_pin.sym} 415 -1008.75 2 1 {name=p22 sig_type=std_logic lab=VIN}
C {devices/lab_pin.sym} 415 -1088.75 2 1 {name=p23 sig_type=std_logic lab=IB}
C {devices/lab_pin.sym} 415 -1068.75 2 1 {name=p24 sig_type=std_logic lab=CLK}
C {devices/lab_pin.sym} 415 -1108.75 2 1 {name=p25 sig_type=std_logic lab=VIN}
C {devices/lab_pin.sym} 415 -1188.75 2 1 {name=p26 sig_type=std_logic lab=IB}
C {devices/lab_pin.sym} 415 -1168.75 2 1 {name=p27 sig_type=std_logic lab=CLK}
C {devices/lab_pin.sym} 415 -1208.75 2 1 {name=p28 sig_type=std_logic lab=VIN}
C {devices/lab_pin.sym} 415 -1288.75 2 1 {name=p29 sig_type=std_logic lab=IB}
C {devices/lab_pin.sym} 415 -1268.75 2 1 {name=p30 sig_type=std_logic lab=CLK}
C {devices/lab_pin.sym} 415 -1308.75 2 1 {name=p31 sig_type=std_logic lab=VIN}
C {devices/lab_pin.sym} 415 -1388.75 2 1 {name=p32 sig_type=std_logic lab=IB}
C {devices/lab_pin.sym} 415 -1368.75 2 1 {name=p33 sig_type=std_logic lab=CLK}
C {devices/lab_pin.sym} 415 -1408.75 2 1 {name=p34 sig_type=std_logic lab=VIN}
C {devices/lab_pin.sym} 415 -1488.75 2 1 {name=p35 sig_type=std_logic lab=IB}
C {devices/lab_pin.sym} 415 -1468.75 2 1 {name=p36 sig_type=std_logic lab=CLK}
C {devices/lab_pin.sym} 415 -1508.75 2 1 {name=p37 sig_type=std_logic lab=VIN}
C {devices/lab_pin.sym} 415 -1588.75 2 1 {name=p38 sig_type=std_logic lab=IB}
C {devices/lab_pin.sym} 415 -1568.75 2 1 {name=p39 sig_type=std_logic lab=CLK}
C {devices/lab_pin.sym} 415 -1608.75 2 1 {name=p42 sig_type=std_logic lab=VIN}
C {devices/lab_pin.sym} 415 -1688.75 2 1 {name=p43 sig_type=std_logic lab=IB}
C {devices/lab_pin.sym} 415 -1668.75 2 1 {name=p44 sig_type=std_logic lab=CLK}
C {devices/lab_pin.sym} 415 -1708.75 2 1 {name=p45 sig_type=std_logic lab=VIN}
C {devices/lab_pin.sym} 415 -1788.75 2 1 {name=p46 sig_type=std_logic lab=IB}
C {devices/lab_pin.sym} 415 -1768.75 2 1 {name=p47 sig_type=std_logic lab=CLK}
C {devices/lab_pin.sym} 415 -1808.75 2 1 {name=p48 sig_type=std_logic lab=VIN}
C {devices/vsource.sym} 15 121.25 0 0 {name=V7 value="PWL(0ns 0.5 230ns 1.7)" savecurrent=false}
C {devices/gnd.sym} 15 191.25 0 0 {name=l19 lab=GND}
C {devices/lab_pin.sym} 15 -48.75 2 0 {name=p133 sig_type=std_logic lab=VIN}
C {devices/res.sym} 15 21.25 0 0 {name=R36
value=1k
footprint=1206
device=resistor
m=1}
C {/foss/designs/Analog_FA23_SP24/strongARM/class_AB_v2_sym.sym} 605 -298.75 0 0 {name=x1}
C {/foss/designs/Analog_FA23_SP24/strongARM/class_AB_v2_sym.sym} 605 -398.75 0 0 {name=x2}
C {/foss/designs/Analog_FA23_SP24/strongARM/class_AB_v2_sym.sym} 605 -498.75 0 0 {name=x3}
C {/foss/designs/Analog_FA23_SP24/strongARM/class_AB_v2_sym.sym} 605 -598.75 0 0 {name=x4}
C {/foss/designs/Analog_FA23_SP24/strongARM/class_AB_v2_sym.sym} 605 -698.75 0 0 {name=x5}
C {/foss/designs/Analog_FA23_SP24/strongARM/class_AB_v2_sym.sym} 605 -798.75 0 0 {name=x6}
C {/foss/designs/Analog_FA23_SP24/strongARM/class_AB_v2_sym.sym} 605 -898.75 0 0 {name=x7}
C {/foss/designs/Analog_FA23_SP24/strongARM/class_AB_v2_sym.sym} 605 -998.75 0 0 {name=x8}
C {/foss/designs/Analog_FA23_SP24/strongARM/class_AB_v2_sym.sym} 605 -1098.75 0 0 {name=x9}
C {/foss/designs/Analog_FA23_SP24/strongARM/class_AB_v2_sym.sym} 605 -1198.75 0 0 {name=x10}
C {/foss/designs/Analog_FA23_SP24/strongARM/class_AB_v2_sym.sym} 605 -1298.75 0 0 {name=x11}
C {/foss/designs/Analog_FA23_SP24/strongARM/class_AB_v2_sym.sym} 605 -1398.75 0 0 {name=x12}
C {/foss/designs/Analog_FA23_SP24/strongARM/class_AB_v2_sym.sym} 605 -1498.75 0 0 {name=x13}
C {/foss/designs/Analog_FA23_SP24/strongARM/class_AB_v2_sym.sym} 605 -1598.75 0 0 {name=x14}
C {/foss/designs/Analog_FA23_SP24/strongARM/class_AB_v2_sym.sym} 605 -1698.75 0 0 {name=x15}
C {/foss/designs/Analog_FA23_SP24/strongARM/class_AB_v2_sym.sym} 605 -1798.75 0 0 {name=x16}
C {/foss/designs/Analog_FA23_SP24/RSlatch/RSfetsym.sym} 1015 -778.75 0 0 {name=x17}
C {devices/code.sym} 895 31.25 0 0 {name=TT_MODELS
only_toplevel=true
format="tcleval(@value )"
value=".lib $::SKYWATER_MODELS/sky130.lib.spice tt
.include $::SKYWATER_STDCELLS/sky130_fd_sc_hd.spice
"
spice_ignore=false
place=header}
C {devices/lab_pin.sym} 1165 -808.75 2 0 {name=p134 sig_type=std_logic lab=VDD}
C {devices/gnd.sym} 1165 -748.75 0 0 {name=l20 lab=GND}
C {/foss/designs/Analog_FA23_SP24/RSlatch/RSfetsym.sym} 1015 -678.75 0 0 {name=x18}
C {devices/gnd.sym} 1165 -648.75 0 0 {name=l21 lab=GND}
C {devices/lab_pin.sym} 1165 -708.75 2 0 {name=p137 sig_type=std_logic lab=VDD}
C {/foss/designs/Analog_FA23_SP24/RSlatch/RSfetsym.sym} 1015 -578.75 0 0 {name=x19}
C {devices/gnd.sym} 1165 -548.75 0 0 {name=l22 lab=GND}
C {devices/lab_pin.sym} 1165 -608.75 2 0 {name=p138 sig_type=std_logic lab=VDD}
C {/foss/designs/Analog_FA23_SP24/RSlatch/RSfetsym.sym} 1015 -478.75 0 0 {name=x20}
C {devices/gnd.sym} 1165 -448.75 0 0 {name=l23 lab=GND}
C {devices/lab_pin.sym} 1165 -508.75 2 0 {name=p139 sig_type=std_logic lab=VDD}
C {/foss/designs/Analog_FA23_SP24/RSlatch/RSfetsym.sym} 1015 -378.75 0 0 {name=x21}
C {devices/gnd.sym} 1165 -348.75 0 0 {name=l24 lab=GND}
C {devices/lab_pin.sym} 1165 -408.75 2 0 {name=p140 sig_type=std_logic lab=VDD}
C {/foss/designs/Analog_FA23_SP24/RSlatch/RSfetsym.sym} 1015 -278.75 0 0 {name=x22}
C {devices/gnd.sym} 1165 -248.75 0 0 {name=l25 lab=GND}
C {devices/lab_pin.sym} 1165 -308.75 2 0 {name=p141 sig_type=std_logic lab=VDD}
C {/foss/designs/Analog_FA23_SP24/RSlatch/RSfetsym.sym} 1015 -878.75 0 0 {name=x23}
C {devices/gnd.sym} 1165 -848.75 0 0 {name=l26 lab=GND}
C {devices/lab_pin.sym} 1165 -908.75 2 0 {name=p142 sig_type=std_logic lab=VDD}
C {/foss/designs/Analog_FA23_SP24/RSlatch/RSfetsym.sym} 1015 -978.75 0 0 {name=x24}
C {devices/gnd.sym} 1165 -948.75 0 0 {name=l27 lab=GND}
C {devices/lab_pin.sym} 1165 -1008.75 2 0 {name=p143 sig_type=std_logic lab=VDD}
C {/foss/designs/Analog_FA23_SP24/RSlatch/RSfetsym.sym} 1015 -1078.75 0 0 {name=x25}
C {devices/gnd.sym} 1165 -1048.75 0 0 {name=l28 lab=GND}
C {devices/lab_pin.sym} 1165 -1108.75 2 0 {name=p144 sig_type=std_logic lab=VDD}
C {/foss/designs/Analog_FA23_SP24/RSlatch/RSfetsym.sym} 1015 -1178.75 0 0 {name=x26}
C {devices/gnd.sym} 1165 -1148.75 0 0 {name=l29 lab=GND}
C {devices/lab_pin.sym} 1165 -1208.75 2 0 {name=p145 sig_type=std_logic lab=VDD}
C {/foss/designs/Analog_FA23_SP24/RSlatch/RSfetsym.sym} 1015 -1278.75 0 0 {name=x27}
C {devices/gnd.sym} 1165 -1248.75 0 0 {name=l30 lab=GND}
C {devices/lab_pin.sym} 1165 -1308.75 2 0 {name=p146 sig_type=std_logic lab=VDD}
C {/foss/designs/Analog_FA23_SP24/RSlatch/RSfetsym.sym} 1015 -1378.75 0 0 {name=x28}
C {devices/gnd.sym} 1165 -1348.75 0 0 {name=l31 lab=GND}
C {devices/lab_pin.sym} 1165 -1408.75 2 0 {name=p147 sig_type=std_logic lab=VDD}
C {/foss/designs/Analog_FA23_SP24/RSlatch/RSfetsym.sym} 1015 -1478.75 0 0 {name=x29}
C {devices/gnd.sym} 1165 -1448.75 0 0 {name=l32 lab=GND}
C {devices/lab_pin.sym} 1165 -1508.75 2 0 {name=p148 sig_type=std_logic lab=VDD}
C {/foss/designs/Analog_FA23_SP24/RSlatch/RSfetsym.sym} 1015 -1578.75 0 0 {name=x30}
C {devices/gnd.sym} 1165 -1548.75 0 0 {name=l33 lab=GND}
C {devices/lab_pin.sym} 1165 -1608.75 2 0 {name=p149 sig_type=std_logic lab=VDD}
C {/foss/designs/Analog_FA23_SP24/RSlatch/RSfetsym.sym} 1015 -1678.75 0 0 {name=x31}
C {devices/gnd.sym} 1165 -1648.75 0 0 {name=l38 lab=GND}
C {devices/lab_pin.sym} 1165 -1708.75 2 0 {name=p150 sig_type=std_logic lab=VDD}
C {/foss/designs/Analog_FA23_SP24/RSlatch/RSfetsym.sym} 1015 -1778.75 0 0 {name=x32}
C {devices/gnd.sym} 1165 -1748.75 0 0 {name=l39 lab=GND}
C {devices/lab_pin.sym} 1165 -1808.75 2 0 {name=p151 sig_type=std_logic lab=VDD}
C {devices/noconn.sym} 1165 -268.75 2 0 {name=l57}
C {devices/noconn.sym} 1165 -368.75 2 0 {name=l58}
C {devices/noconn.sym} 1165 -468.75 2 0 {name=l59}
C {devices/noconn.sym} 1165 -568.75 2 0 {name=l60}
C {devices/noconn.sym} 1165 -668.75 2 0 {name=l61}
C {devices/noconn.sym} 1165 -768.75 2 0 {name=l62}
C {devices/noconn.sym} 1165 -868.75 2 0 {name=l63}
C {devices/noconn.sym} 1165 -968.75 2 0 {name=l64}
C {devices/noconn.sym} 1165 -1068.75 2 0 {name=l65}
C {devices/noconn.sym} 1165 -1168.75 2 0 {name=l66}
C {devices/noconn.sym} 1165 -1268.75 2 0 {name=l67}
C {devices/noconn.sym} 1165 -1368.75 2 0 {name=l68}
C {devices/noconn.sym} 1165 -1468.75 2 0 {name=l69}
C {devices/noconn.sym} 1165 -1568.75 2 0 {name=l70}
C {devices/noconn.sym} 1165 -1668.75 2 0 {name=l71}
C {devices/noconn.sym} 1165 -1768.75 2 0 {name=l72}
C {devices/lab_pin.sym} 2006.25 -1660 2 0 {name=p158 sig_type=std_logic lab=OUT2}
C {devices/lab_pin.sym} 2006.25 -1640 2 0 {name=p159 sig_type=std_logic lab=OUT1}
C {devices/lab_pin.sym} 2006.25 -1620 2 0 {name=p160 sig_type=std_logic lab=OUT0}
C {devices/lab_pin.sym} 1706.25 -1700 0 0 {name=p161 sig_type=std_logic lab=VDD}
C {devices/lab_pin.sym} 2006.25 -1680 2 0 {name=p162 sig_type=std_logic lab=OUT3}
C {/foss/designs/Analog_FA23_SP24/PriorityEncoder/32to5_Priority_Encoder_v0p2p2.sym} 1856.25 -1380 0 0 {name=x33}
C {devices/vdd.sym} 235 351.25 0 0 {name=l80 lab=VDD}
C {devices/lab_pin.sym} 105 430 1 0 {name=p164 sig_type=std_logic lab=GND}
C {devices/gnd.sym} 105 460 0 0 {name=l81 lab=GND}
C {devices/gnd.sym} 1706.25 -1680 0 0 {name=l56 lab=GND}
C {devices/gnd.sym} 1706.25 -1660 0 0 {name=l73 lab=GND}
C {devices/gnd.sym} 1706.25 -1640 0 0 {name=l74 lab=GND}
C {devices/gnd.sym} 1706.25 -1620 0 0 {name=l75 lab=GND}
C {devices/gnd.sym} 1706.25 -1600 0 0 {name=l76 lab=GND}
C {devices/gnd.sym} 1706.25 -1580 0 0 {name=l77 lab=GND}
C {devices/gnd.sym} 1706.25 -1560 0 0 {name=l78 lab=GND}
C {devices/gnd.sym} 1706.25 -1540 0 0 {name=l79 lab=GND}
C {devices/gnd.sym} 1706.25 -1520 0 0 {name=l82 lab=GND}
C {devices/gnd.sym} 1706.25 -1500 0 0 {name=l83 lab=GND}
C {devices/gnd.sym} 1706.25 -1480 0 0 {name=l84 lab=GND}
C {devices/gnd.sym} 1706.25 -1460 0 0 {name=l85 lab=GND}
C {devices/gnd.sym} 1706.25 -1440 0 0 {name=l86 lab=GND}
C {devices/gnd.sym} 1706.25 -1420 0 0 {name=l87 lab=GND}
C {devices/gnd.sym} 1706.25 -1400 0 0 {name=l88 lab=GND}
C {devices/gnd.sym} 1706.25 -1380 0 0 {name=l40 lab=GND}
